VERSION 5.7 ;
  NOWIREEXTENSIONATPIN ON ;
  DIVIDERCHAR "/" ;
  BUSBITCHARS "[]" ;
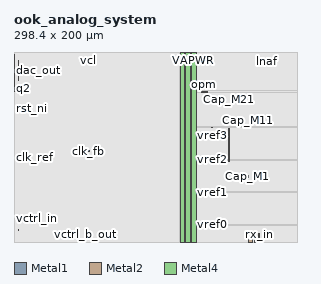
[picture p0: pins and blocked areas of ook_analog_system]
MACRO ook_analog_system
  CLASS BLOCK ;
  FOREIGN ook_analog_system ;
  ORIGIN -201.600 0.000 ;
  SIZE 298.400 BY 200.000 ;
  PIN vcl
    PORT
      LAYER Metal1 ;
        RECT 276.890 193.130 283.240 193.570 ;
    END
  END vcl
  PIN Cap_M21
    ANTENNAGATEAREA 9.000000 ;
    PORT
      LAYER Metal1 ;
        RECT 427.520 150.340 427.650 150.470 ;
    END
  END Cap_M21
  PIN Cap_M2
    ANTENNAGATEAREA 9.000000 ;
    PORT
      LAYER Metal1 ;
        RECT 426.910 84.650 428.110 119.980 ;
    END
  END Cap_M2
  PIN vctrl_out
    ANTENNAGATEAREA 2.535000 ;
    ANTENNADIFFAREA 0.708600 ;
    PORT
      LAYER Metal1 ;
        RECT 213.935 4.850 214.190 5.140 ;
    END
  END vctrl_out
  PIN vctrl_b_out
    ANTENNAGATEAREA 2.535000 ;
    ANTENNADIFFAREA 0.708600 ;
    PORT
      LAYER Metal1 ;
        RECT 276.290 4.850 276.545 5.140 ;
    END
  END vctrl_b_out
  PIN rx_in
    ANTENNAGATEAREA 9.000000 ;
    PORT
      LAYER Metal2 ;
        RECT 459.240 0.000 460.440 8.800 ;
    END
  END rx_in
  PIN ACC_CAP
    ANTENNAGATEAREA 42.000000 ;
    ANTENNADIFFAREA 4.400000 ;
    PORT
      LAYER Metal2 ;
        RECT 454.540 0.000 455.540 7.080 ;
    END
  END ACC_CAP
  PIN tx_out
    ANTENNAGATEAREA 1.040000 ;
    ANTENNADIFFAREA 61.039997 ;
    PORT
      LAYER Metal2 ;
        RECT 448.240 0.000 452.240 5.350 ;
    END
  END tx_out
  PIN Cap_M1
    ANTENNAGATEAREA 2.350000 ;
    ANTENNADIFFAREA 6.904000 ;
    PORT
      LAYER Metal2 ;
        RECT 447.600 68.360 448.210 69.560 ;
    END
  END Cap_M1
  PIN Cap_M11
    ANTENNAGATEAREA 2.350000 ;
    ANTENNADIFFAREA 6.904000 ;
    PORT
      LAYER Metal2 ;
        RECT 448.340 136.460 448.470 136.590 ;
    END
  END Cap_M11
  PIN lnaf
    ANTENNAGATEAREA 2.350000 ;
    ANTENNADIFFAREA 6.904000 ;
    PORT
      LAYER Metal2 ;
        RECT 466.595 189.460 468.670 190.660 ;
    END
  END lnaf
  PIN q3
    ANTENNAGATEAREA 16.000000 ;
    ANTENNADIFFAREA 4.080000 ;
    PORT
      LAYER Metal2 ;
        RECT 202.170 161.980 202.610 197.420 ;
    END
  END q3
  PIN q2
    ANTENNAGATEAREA 16.000000 ;
    ANTENNADIFFAREA 4.080000 ;
    PORT
      LAYER Metal2 ;
        RECT 202.170 161.120 203.490 161.560 ;
    END
  END q2
  PIN q1
    ANTENNAGATEAREA 16.000000 ;
    ANTENNADIFFAREA 4.080000 ;
    PORT
      LAYER Metal2 ;
        RECT 202.170 159.970 204.390 160.410 ;
    END
  END q1
  PIN q0
    ANTENNAGATEAREA 16.000000 ;
    ANTENNADIFFAREA 4.080000 ;
    PORT
      LAYER Metal2 ;
        RECT 202.170 158.930 205.240 159.370 ;
    END
  END q0
  PIN clk_fb
    ANTENNAGATEAREA 0.891800 ;
    ANTENNADIFFAREA 11.575000 ;
    PORT
      LAYER Metal2 ;
        RECT 279.960 95.510 280.620 95.950 ;
    END
  END clk_fb
  PIN rst_ni
    ANTENNAGATEAREA 0.180700 ;
    PORT
      LAYER Metal2 ;
        RECT 206.400 140.170 206.800 140.570 ;
    END
  END rst_ni
  PIN clk_ref
    ANTENNAGATEAREA 0.725400 ;
    PORT
      LAYER Metal2 ;
        RECT 206.400 88.330 206.800 88.730 ;
    END
  END clk_ref
  PIN vctrl_in
    ANTENNAGATEAREA 0.180700 ;
    PORT
      LAYER Metal2 ;
        RECT 206.400 16.330 206.800 16.730 ;
    END
  END vctrl_in
  PIN vctrl_b_in
    ANTENNAGATEAREA 0.180700 ;
    PORT
      LAYER Metal2 ;
        RECT 206.400 12.490 206.800 12.890 ;
    END
  END vctrl_b_in
  PIN dac_out
    ANTENNADIFFAREA 0.708600 ;
    PORT
      LAYER Metal2 ;
        RECT 206.380 170.390 206.820 191.190 ;
    END
  END dac_out
  PIN opm
    ANTENNAGATEAREA 1.000000 ;
    ANTENNADIFFAREA 8.728400 ;
    PORT
      LAYER Metal4 ;
        RECT 399.010 157.695 405.150 158.895 ;
    END
  END opm
  PIN vref3
    ANTENNAGATEAREA 8.000000 ;
    PORT
      LAYER Metal4 ;
        RECT 409.750 120.660 410.770 120.860 ;
    END
  END vref3
  PIN vref2
    ANTENNAGATEAREA 8.000000 ;
    PORT
      LAYER Metal4 ;
        RECT 409.750 86.460 410.770 86.660 ;
    END
  END vref2
  PIN vref1
    ANTENNAGATEAREA 8.000000 ;
    PORT
      LAYER Metal4 ;
        RECT 409.760 52.260 410.780 52.460 ;
    END
  END vref1
  PIN vref0
    ANTENNAGATEAREA 8.000000 ;
    PORT
      LAYER Metal4 ;
        RECT 410.745 18.045 410.875 18.175 ;
    END
  END vref0
  PIN VAPWR
    ANTENNAGATEAREA 67.250000 ;
    ANTENNADIFFAREA 198.890396 ;
    PORT
      LAYER Metal4 ;
        RECT 388.395 0.000 393.395 200.000 ;
    END
  END VAPWR
  PIN VGND
    ANTENNAGATEAREA 225.898987 ;
    ANTENNADIFFAREA 1465.572754 ;
    PORT
      LAYER Metal4 ;
        RECT 382.395 0.000 387.395 200.000 ;
    END
  END VGND
  PIN VPWR
    ANTENNAGATEAREA 105.572495 ;
    ANTENNADIFFAREA 1474.200439 ;
    PORT
      LAYER Metal4 ;
        RECT 376.395 0.000 381.395 200.000 ;
    END
  END VPWR
  OBS
      LAYER GatPoly ;
        RECT 207.290 4.530 494.175 196.640 ;
      LAYER Metal1 ;
        RECT 207.220 193.750 496.410 196.500 ;
        RECT 207.220 192.950 276.710 193.750 ;
        RECT 283.420 192.950 496.410 193.750 ;
        RECT 207.220 150.650 496.410 192.950 ;
        RECT 207.220 150.160 427.340 150.650 ;
        RECT 427.830 150.160 496.410 150.650 ;
        RECT 207.220 120.160 496.410 150.160 ;
        RECT 207.220 84.470 426.730 120.160 ;
        RECT 428.290 84.470 496.410 120.160 ;
        RECT 207.220 5.320 496.410 84.470 ;
        RECT 207.220 4.670 213.755 5.320 ;
        RECT 214.370 4.670 276.110 5.320 ;
        RECT 276.725 4.670 496.410 5.320 ;
        RECT 207.220 1.910 496.410 4.670 ;
      LAYER Metal2 ;
        RECT 202.610 197.630 498.630 198.170 ;
        RECT 202.820 191.400 498.630 197.630 ;
        RECT 202.820 170.180 206.170 191.400 ;
        RECT 207.030 190.870 498.630 191.400 ;
        RECT 207.030 189.250 466.385 190.870 ;
        RECT 468.880 189.250 498.630 190.870 ;
        RECT 207.030 170.180 498.630 189.250 ;
        RECT 202.820 161.770 498.630 170.180 ;
        RECT 203.700 160.910 498.630 161.770 ;
        RECT 202.610 160.620 498.630 160.910 ;
        RECT 204.600 159.760 498.630 160.620 ;
        RECT 202.610 159.580 498.630 159.760 ;
        RECT 205.450 158.720 498.630 159.580 ;
        RECT 202.610 140.780 498.630 158.720 ;
        RECT 202.610 139.960 206.190 140.780 ;
        RECT 207.010 139.960 498.630 140.780 ;
        RECT 202.610 136.800 498.630 139.960 ;
        RECT 202.610 136.250 448.130 136.800 ;
        RECT 448.680 136.250 498.630 136.800 ;
        RECT 202.610 96.160 498.630 136.250 ;
        RECT 202.610 95.300 279.750 96.160 ;
        RECT 280.830 95.300 498.630 96.160 ;
        RECT 202.610 88.940 498.630 95.300 ;
        RECT 202.610 88.120 206.190 88.940 ;
        RECT 207.010 88.120 498.630 88.940 ;
        RECT 202.610 69.770 498.630 88.120 ;
        RECT 202.610 68.150 447.390 69.770 ;
        RECT 448.420 68.150 498.630 69.770 ;
        RECT 202.610 16.940 498.630 68.150 ;
        RECT 202.610 16.120 206.190 16.940 ;
        RECT 207.010 16.120 498.630 16.940 ;
        RECT 202.610 13.100 498.630 16.120 ;
        RECT 202.610 12.280 206.190 13.100 ;
        RECT 207.010 12.280 498.630 13.100 ;
        RECT 202.610 9.010 498.630 12.280 ;
        RECT 202.610 7.290 459.030 9.010 ;
        RECT 202.610 5.560 454.330 7.290 ;
        RECT 202.610 1.350 448.030 5.560 ;
        RECT 452.450 1.350 454.330 5.560 ;
        RECT 455.750 1.350 459.030 7.290 ;
        RECT 460.650 1.350 498.630 9.010 ;
      LAYER Metal3 ;
        RECT 204.170 0.000 499.970 200.000 ;
      LAYER Metal4 ;
        RECT 201.600 0.000 376.185 200.000 ;
        RECT 381.605 0.000 382.185 200.000 ;
        RECT 387.605 0.000 388.185 200.000 ;
        RECT 393.605 159.105 500.000 200.000 ;
        RECT 393.605 157.485 398.800 159.105 ;
        RECT 405.360 157.485 500.000 159.105 ;
        RECT 393.605 121.070 500.000 157.485 ;
        RECT 393.605 120.450 409.540 121.070 ;
        RECT 410.980 120.450 500.000 121.070 ;
        RECT 393.605 86.870 500.000 120.450 ;
        RECT 393.605 86.250 409.540 86.870 ;
        RECT 410.980 86.250 500.000 86.870 ;
        RECT 393.605 52.670 500.000 86.250 ;
        RECT 393.605 52.050 409.550 52.670 ;
        RECT 410.990 52.050 500.000 52.670 ;
        RECT 393.605 18.385 500.000 52.050 ;
        RECT 393.605 17.835 410.535 18.385 ;
        RECT 411.085 17.835 500.000 18.385 ;
        RECT 393.605 0.000 500.000 17.835 ;
  END
END ook_analog_system
END LIBRARY

